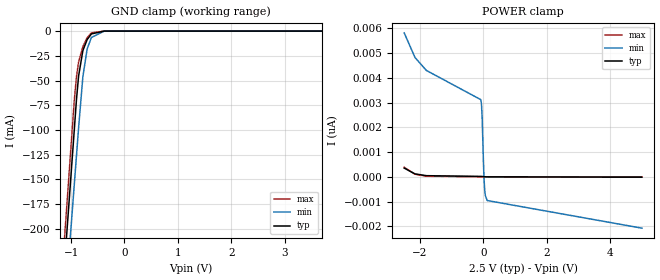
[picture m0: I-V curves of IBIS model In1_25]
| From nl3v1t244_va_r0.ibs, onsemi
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|//////////////////////////////////////////////////////////////////////////////
|//////////////////////////////////////////////////////////////////////////////
[Model]  In1_25
Model_type Input
Vinh =  1.6
Vinl =  0.7
|  variable   typ   min   max
C_comp   6.2pF   6.2pF   6.2pF
|//////////////////////////////////////////////////////////////////////////////
[Temperature Range]   25   125   -40
|//////////////////////////////////////////////////////////////////////////////
[Voltage Range]   2.50V   2.30V   2.70V
|//////////////////////////////////////////////////////////////////////////////
[POWER Clamp Reference] 2.50V   2.30V   2.70V
|//////////////////////////////////////////////////////////////////////////////
[GND Clamp Reference]   0V   0V   0V
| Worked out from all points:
|   GND clamp passes 1 mA (typ) near -0.56 V on its own axis
|//////////////////////////////////////////////////////////////////////////////
[GND Clamp]
|   Voltage   I(typ)   I(min)   I(max)
-2.5V     -1.26A     -1.263A    -1.257A
-1.18V    -278mA     -325.3mA   -252.2mA
-1.1V     -218.4mA   -268.4mA   -191.3mA
-1.04V    -173.8mA   -225.8mA   -145.6mA
-940mV    -99.42mA   -154.7mA   -69.51mA
-900mV    -69.33mA   -126.3mA   -46.26mA
-860mV    -45.54mA   -97.9mA    -31.41mA
-780mV    -19.75mA   -46.28mA   -15.71mA
-700mV    -8.683mA   -18.18mA   -6.734mA
-620mV    -2.857mA   -6.467mA   -1.78mA
-380mV    -1.788uA   -32.75uA   -260.7nA
5V        2.467pA    -432.4pA   -188.9fA
|//////////////////////////////////////////////////////////////////////////////
[POWER Clamp]
|   Voltage   I(typ)   I(min)   I(max)
-2.5V     351.8pA    5.817nA    384.2pA
-2.16V    116.6pA    4.824nA    103.9pA
-1.8V     44.68pA    4.299nA    23pA
-80mV     15.31pA    3.116nA    -251.8fA
-60mV     13.95pA    2.909nA    -252.4fA
-40mV     12.05pA    2.398nA    -252.9fA
0V        7.496pA    617.6pA    -254.1fA
20mV      5.213pA    -116.4pA   -254.6fA
40mV      3.089pA    -528pA     -255.2fA
60mV      1.116pA    -760.2pA   -255.8fA
120mV     -2.571pA   -960.1pA   -257.5fA
5V        -17.02pA   -2.077nA   -395.8fA
